One B-rep face of a CAD part: STEP entity #150.
In plain terms, the planar face has unit normal (0, 1, 0).
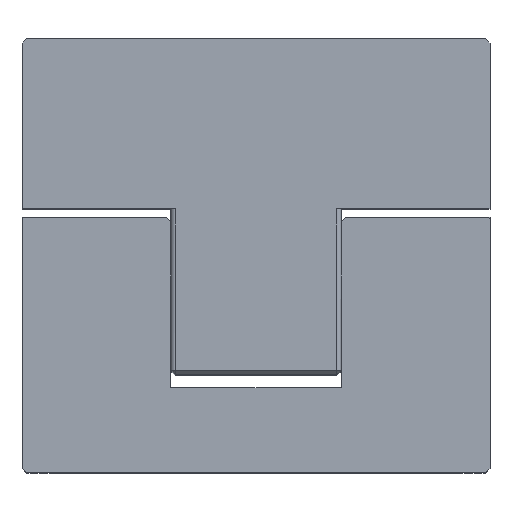
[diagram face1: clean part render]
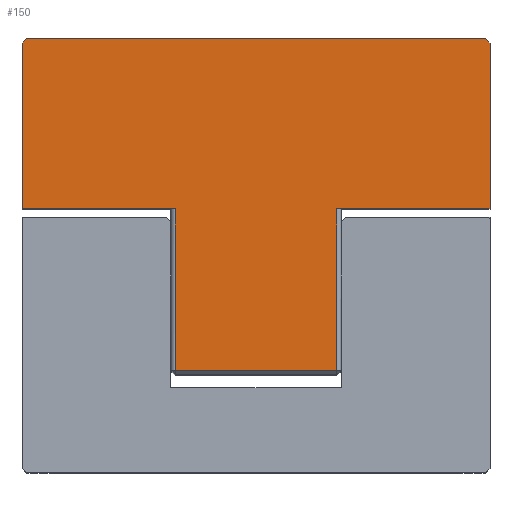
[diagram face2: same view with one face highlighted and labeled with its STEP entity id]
Its self-contained STEP definition (entity closure, numbers rounded to 3 decimals):
#63=CARTESIAN_POINT('Axis2P3D Location',(0.,18.,0.)) ;
#68=CARTESIAN_POINT('Line Origine',(9.5,18.,29.5)) ;
#72=CARTESIAN_POINT('Vertex',(9.5,18.,39.)) ;
#74=CARTESIAN_POINT('Vertex',(9.5,18.,20.)) ;
#77=CARTESIAN_POINT('Line Origine',(18.5,18.,20.)) ;
#81=CARTESIAN_POINT('Vertex',(27.5,18.,20.)) ;
#84=CARTESIAN_POINT('Line Origine',(27.5,18.,10.25)) ;
#88=CARTESIAN_POINT('Vertex',(27.5,18.,0.5)) ;
#91=CARTESIAN_POINT('Line Origine',(27.25,18.,0.25)) ;
#95=CARTESIAN_POINT('Vertex',(27.,18.,0.)) ;
#98=CARTESIAN_POINT('Line Origine',(0.,18.,0.)) ;
#102=CARTESIAN_POINT('Vertex',(-27.,18.,0.)) ;
#105=CARTESIAN_POINT('Line Origine',(-27.25,18.,0.25)) ;
#109=CARTESIAN_POINT('Vertex',(-27.5,18.,0.5)) ;
#112=CARTESIAN_POINT('Line Origine',(-27.5,18.,10.25)) ;
#116=CARTESIAN_POINT('Vertex',(-27.5,18.,20.)) ;
#119=CARTESIAN_POINT('Line Origine',(-18.5,18.,20.)) ;
#123=CARTESIAN_POINT('Vertex',(-9.5,18.,20.)) ;
#126=CARTESIAN_POINT('Line Origine',(-9.5,18.,29.5)) ;
#130=CARTESIAN_POINT('Vertex',(-9.5,18.,39.)) ;
#133=CARTESIAN_POINT('Line Origine',(0.,18.,39.)) ;
#64=DIRECTION('Axis2P3D Direction',(0.,-1.,0.)) ;
#65=DIRECTION('Axis2P3D XDirection',(1.,0.,0.)) ;
#69=DIRECTION('Vector Direction',(0.,0.,-1.)) ;
#78=DIRECTION('Vector Direction',(1.,0.,0.)) ;
#85=DIRECTION('Vector Direction',(0.,0.,1.)) ;
#92=DIRECTION('Vector Direction',(-0.707,0.,-0.707)) ;
#99=DIRECTION('Vector Direction',(1.,0.,0.)) ;
#106=DIRECTION('Vector Direction',(-0.707,0.,0.707)) ;
#113=DIRECTION('Vector Direction',(0.,0.,-1.)) ;
#120=DIRECTION('Vector Direction',(1.,0.,0.)) ;
#127=DIRECTION('Vector Direction',(0.,0.,1.)) ;
#134=DIRECTION('Vector Direction',(1.,0.,0.)) ;
#66=AXIS2_PLACEMENT_3D('Plane Axis2P3D',#63,#64,#65) ;
#139=ORIENTED_EDGE('',*,*,#76,.T.) ;
#140=ORIENTED_EDGE('',*,*,#83,.T.) ;
#141=ORIENTED_EDGE('',*,*,#90,.F.) ;
#142=ORIENTED_EDGE('',*,*,#97,.T.) ;
#143=ORIENTED_EDGE('',*,*,#104,.F.) ;
#144=ORIENTED_EDGE('',*,*,#111,.T.) ;
#145=ORIENTED_EDGE('',*,*,#118,.F.) ;
#146=ORIENTED_EDGE('',*,*,#125,.T.) ;
#147=ORIENTED_EDGE('',*,*,#132,.T.) ;
#148=ORIENTED_EDGE('',*,*,#137,.T.) ;
#70=VECTOR('Line Direction',#69,1.) ;
#79=VECTOR('Line Direction',#78,1.) ;
#86=VECTOR('Line Direction',#85,1.) ;
#93=VECTOR('Line Direction',#92,1.) ;
#100=VECTOR('Line Direction',#99,1.) ;
#107=VECTOR('Line Direction',#106,1.) ;
#114=VECTOR('Line Direction',#113,1.) ;
#121=VECTOR('Line Direction',#120,1.) ;
#128=VECTOR('Line Direction',#127,1.) ;
#135=VECTOR('Line Direction',#134,1.) ;
#150=ADVANCED_FACE('MANIFOLD_SOLID_BREP #4927',(#149),#67,.F.) ;
#76=EDGE_CURVE('',#73,#75,#71,.T.) ;
#83=EDGE_CURVE('',#75,#82,#80,.T.) ;
#90=EDGE_CURVE('',#89,#82,#87,.T.) ;
#97=EDGE_CURVE('',#89,#96,#94,.T.) ;
#104=EDGE_CURVE('',#103,#96,#101,.T.) ;
#111=EDGE_CURVE('',#103,#110,#108,.T.) ;
#118=EDGE_CURVE('',#117,#110,#115,.T.) ;
#125=EDGE_CURVE('',#117,#124,#122,.T.) ;
#132=EDGE_CURVE('',#124,#131,#129,.T.) ;
#137=EDGE_CURVE('',#131,#73,#136,.T.) ;
#138=EDGE_LOOP('',(#139,#140,#141,#142,#143,#144,#145,#146,#147,#148)) ;
#149=FACE_OUTER_BOUND('',#138,.T.) ;
#71=LINE('Line',#68,#70) ;
#80=LINE('Line',#77,#79) ;
#87=LINE('Line',#84,#86) ;
#94=LINE('Line',#91,#93) ;
#101=LINE('Line',#98,#100) ;
#108=LINE('Line',#105,#107) ;
#115=LINE('Line',#112,#114) ;
#122=LINE('Line',#119,#121) ;
#129=LINE('Line',#126,#128) ;
#136=LINE('Line',#133,#135) ;
#67=PLANE('Plane',#66) ;
#73=VERTEX_POINT('',#72) ;
#75=VERTEX_POINT('',#74) ;
#82=VERTEX_POINT('',#81) ;
#89=VERTEX_POINT('',#88) ;
#96=VERTEX_POINT('',#95) ;
#103=VERTEX_POINT('',#102) ;
#110=VERTEX_POINT('',#109) ;
#117=VERTEX_POINT('',#116) ;
#124=VERTEX_POINT('',#123) ;
#131=VERTEX_POINT('',#130) ;
